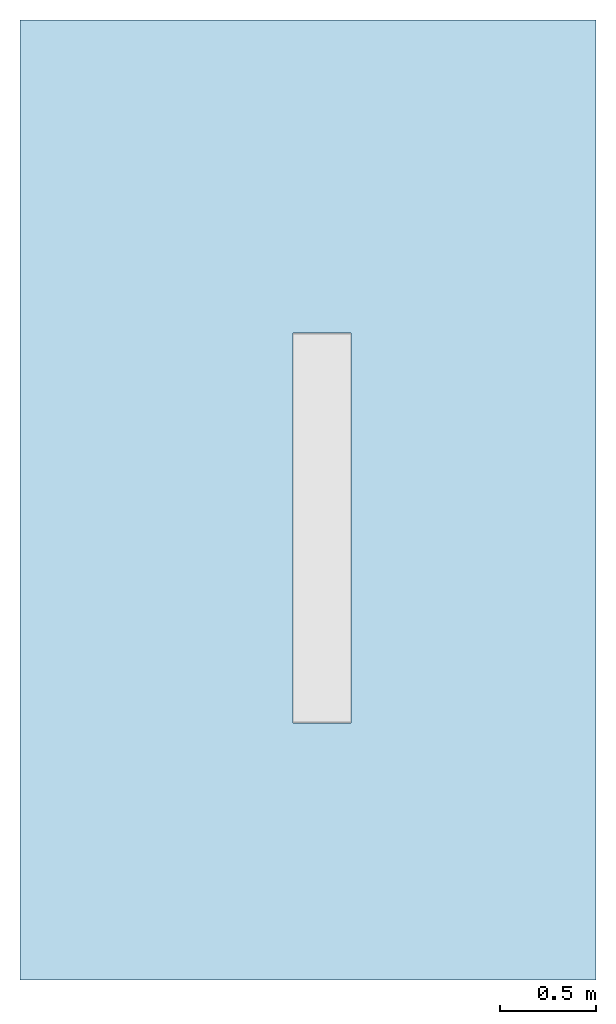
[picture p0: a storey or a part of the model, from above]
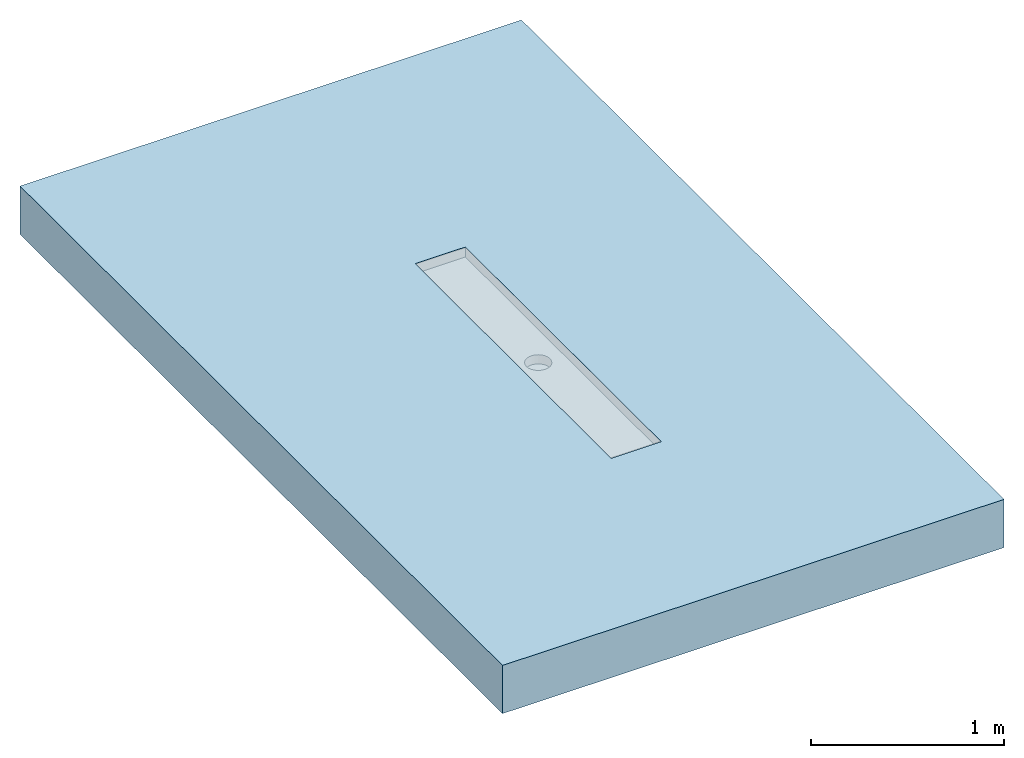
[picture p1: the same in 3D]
Properties of the parts of a building model (IFC2X3)

# File
Description: ViewDefinition [CoordinationView]
File name: Project Number
Time: 2016-11-22T10:36:35
Written by: The EXPRESS Data Manager Version 5.01.0100.02.64mod : 6 Jun 2012
Made in: 20130308_1515(x64) - Exporter 2014.0.2013.0308 - Default UI
Comment: STEP Physical File produced by: The EXPRESS Data Manager Version 5.01.0100.02.64mod : 6 Jun 2012 * Module: EDMstepFileFactory/EDMstandAlone * Creation date: Tue Nov 22 10:36:35 2016 * Host: IN-BLR-PC-0012 * Database: C:\Users\pakumar\AppData\Local\Temp\{E9B9E66B-7367-4930-94AA-0650668612E0}\ifc * Database version: 5507 * Database creation date: Tue Nov 22 10:36:34 2016 * Schema: IFC2X3 * Model: DataRepository.ifc * Model creation date: Tue Nov 22 10:36:34 2016 * Header model: DataRepository.ifc_HeaderModel * Header model creation date: Tue Nov 22 10:36:34 2016 * EDMuser: sdai-user * EDMgroup: sdai-group * License ID and type: 5605 : Permanent license. Expiry date: * EDMstepFileFactory options: 020000

# IfcProject, Project Number
LongName: Project Name; Phase: Project Status

# IfcSite, Default
RefLatitude: 42, 21, 30, 344238; RefLongitude: -71, -3, -35, -194702; RefElevation: 0 mm

# IfcBuilding
Pset_BuildingCommon - NumberOfStoreys: 1
Other - Project Status: Project Status; Client Name: Owner; Project Issue Date: Issue Date; Project Number: Project Number; Project Name: Project Name; Project Address: Enter address here

# IfcBuildingStorey, Level 1
LongName: Level 1; Elevation: 0 mm
Constraints - Elevation Base: Project Base Point; Elevation: 0 mm
Graphics - Color: 0; Symbol at End 1 Default: no; Symbol: Level Head - Circle: Level Head - Circle; Line Pattern: Grid Line 1/2"; Symbol at End 2 Default: yes; Line Weight: 1
Dimensions - Computation Height: 0 mm
Identity Data - Name: Level 1; Building Story: yes; Structural: no

# IfcFlowTerminal: 416618 - Hygienic Standard Channel - with Gully 157 - 2000mm LG - 300mm Wide, ACO Tray Channel - Hygienic - Standard - 300mm Wide:416618 - Hygienic Standard Channel - with Gully 157 - 2000mm LG - 300mm Wide:552951
In: Level 1
Material: Stainless Steel AISI 304, Stainless Steel AISI 304 - Grating
Other - Invert Depth Detail: 51.5 mm; 416618 - Hygienic Standard Channel - 2000mm LG - 300mm Wide: yes; Flow: 0.0988811 m3/s; 416619 - Hygienic Standard Channel - 3000mm LG - 300mm Wide: no; Spigot Outlets Channels: yes; 416615 - Hygienic Standard Channel - 600mm LG - 300mm Wide: no; 416620 - Hygienic Standard Channel - 4000mm LG - 300mm Wide: no; 416614 - Hygienic Standard Channel - 300mm LG - 300mm Wide: no; 416617 - Hygienic Standard Channel - 1500mm LG - 300mm Wide: no; Number mesh: 82; 416616 - Hygienic Standard Channel - 1000mm LG - 300mm Wide: no
Constraints - Level: Level: Level 1
Construction - 416884 - 268 x 298mm - Mesh Grating - L15 - Stainless Steel 1.4301: no; 416812 - 268 x 298mm - Ladder Grating - R50 - Stainless Steel 1.4301: no; 416866 - 268 x 499mm - Mesh Grating - L15 - Stainless Steel 1.4301: no; 416946 - 268 x 299mm - Casted Grating - M125 - Stainless Steel 1.4301: yes; 416864 - 268 x 298mm - Mesh Grating - L15 - Stainless Steel 1.4301: no; 416886 - 268 x 499mm - Mesh Grating - L15 - Stainless Steel 1.4301: no; 416945 - 268 x 499mm - Casted Grating - M125 - Stainless Steel 1.4301: no; 416818 - 268 x 499mm - Ladder Grating - M125 - Stainless Steel 1.4301: no; 416816 - 268 x 298mm - Ladder Grating - M125 - Stainless Steel 1.4301: no; 416814 - 268 x 499mm - Ladder Grating - R50 - Stainless Steel 1.4301: no; Detail - Outlet 142mm: yes; Grating: yes; Detail - Outlet 200: no
Mechanical - System Classification: Sanitary
Phasing - Phase Created: New Construction
Identity Data - Mark: 47; Manufacturer: ACO Building Drainage; Telephone: +44 (0)1462 816666; Watermark1: This file is the property of ACO Technologies PLC.; Fax: +44 (0)1462 851490; Cost: 0; Watermark2: This file is water marked and users are prohibited to reproduce, adapt, distribute this information.; Website: www.acobd.com; E-mail Sales: abdcommercial@aco.co.uk; Watermarked With: BIM Manager Premium Suite.; Watermarked By: www.acobd.com; E-mail Technical: abdtechnical@aco.co.uk; Address: ACO Business Centre, Caxton Road, Bedford, MK41 0LF
Pset_ManufacturerTypeInformation - Manufacturer: ACO Building Drainage
General - Foul air trap Recyclable: Fully recyclable; Price: POA - contact ACO; Load Class: A15 - C250 (EN 1253); Weight (Kg): 10.5; Channel Colour: passivated stainless steel surface ( matt grey); Maintenance guidelines: http://issuu.com/acobuildingdrainage/docs/aco_hygiene_first_catalogue/17?e=0; Product Code: 416618; Channel Dimension: 300 x 2030; Channel Material: Stainless steel 1.4301 (EN 10088); Installation guidelines: http://issuu.com/acobuildingdrainage/docs/aco_hygiene_first_catalogue/17?e=0; Channel Recycled material content: 20 - 30 %; Product Description: ACO Hygiene First Standard Kitchen Tray Channel 300 x 2030 / 142 Dia Outlet & Foul Air Trap; Product Type: Standard Kitchen Tray Channel; Product Standard: EN 1253 / EN 1672 / EN ISO 14159; Foul air trap Recycled material content: 0%; Product Range: ACO Hygiene First; Outlet Diameter (mm): 142; Foul air trap seal Colour: Black; Channel Recyclable: Fully recyclable; Foul air trap seal Material: NBR
Model Properties - Grating Product Code 416866: Load Class L 15 (EN 1253) - Mesh Grate - Stainless steel 1.4301 (EN 10088) - 268 x 499 - 3.4kg; Grating Product Code 416816: N/A; Grating Product Code 416886: Load Class L 15 (EN 1253) - Mesh Grate - Stainless steel 1.4301 (EN 10088) - 268 x 499 - 3.5kg; Grating Product Code 416812: N/A; Grating Product Code 416945: Load Class M 125 (EN 1253) - Cast Grate - Stainless steel 1.4301 (EN 10088) - 268 x 499 - 9kg; Grating Product Code 416884: N/A; Grating Product Code 416818: Load Class M 125 (EN 1253) - Ladder Grate - Stainless steel 1.4301 (EN 10088) - 268 x 499 - 6.8kg; Grating Product Code 416946: N/A; Grating Product Code 416814: Load Class R 50 (EN 1253) - Ladder Grate - Stainless steel 1.4301 (EN 10088) - 268 x 499 - 4.2kg; Grating Product Code 416864: N/A
Dimensions - End Plate: 2000 mm; Length Channel: -1970 mm; Floor Cut Void Height: 62.8 mm; x: -2015 mm; Grating Length: 499 mm; Outside Outlet Rad: 71 mm; Grating Void Cut Length: 500 mm; Depth: 29 mm; Outlet: 142 mm; Inside Outlet Rad: 66 mm; Invert Depth: 50 mm; Endplate Position: 2000 mm; End Connection Plate Start: -1970 mm; Number of gratings: 4; Spigot Distance: 1000 mm; Grating Height: 21 mm; End Connection Plate End: -2000 mm

# IfcOpeningElement: Recess
In: Level 1
Structural - Structural: no; Enable Analytical Model: no
Phasing - Phase Created: New Construction
Constraints - Level: Level: Level 1; Height Offset From Level: 0 mm; Room Bounding: yes; Related to Mass: no
Dimensions - Area: 161.459 ft2; Thickness: 304.8 mm; Volume: 160.076 ft3; Perimeter: 16000 mm
Analytical Properties - Absorptance: 0.7; Roughness: 3
Identity Data - Assembly Code: B1010; Assembly Description: Floor Construction
Construction - Function: Interior; Default Thickness: 304.8 mm
Graphics - Coarse Scale Fill Color: 0

# IfcSlab: Floor:Generic - 12", Floor:Generic - 12":184145
In: Level 1
PredefinedType: FLOOR; Material: Default Floor 304.8 mm
Structural - Structural: no; Enable Analytical Model: no
Phasing - Phase Created: New Construction
Constraints - Level: Level: Level 1; Height Offset From Level: 0 mm; Room Bounding: yes; Related to Mass: no
Dimensions - Area: 161.459 ft2; Thickness: 304.8 mm; Volume: 160.076 ft3; Perimeter: 16000 mm
Pset_SlabCommon - Reference: Generic - 12"; IsExternal: no; LoadBearing: yes
Analytical Properties - Absorptance: 0.7; Roughness: 3
Identity Data - Assembly Code: B1010; Assembly Description: Floor Construction
Construction - Function: Interior; Default Thickness: 304.8 mm
Graphics - Coarse Scale Fill Color: 0
